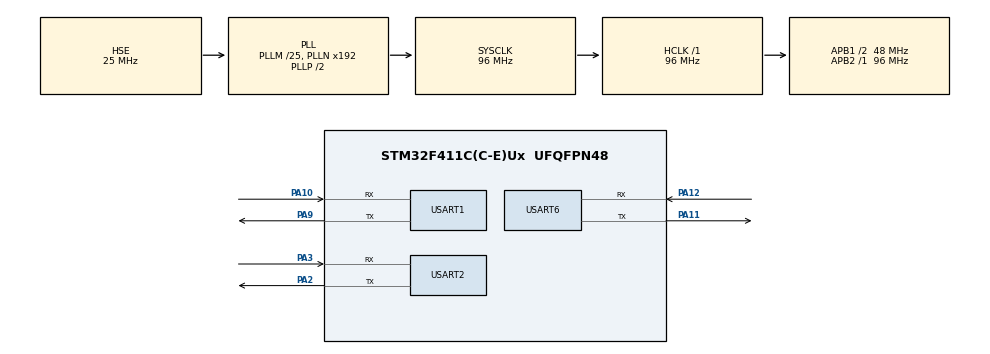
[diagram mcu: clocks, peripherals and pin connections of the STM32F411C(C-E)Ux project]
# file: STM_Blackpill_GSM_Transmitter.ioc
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Dma.Request0=USART1_TX
Dma.USART1_TX.0.Direction=DMA_MEMORY_TO_PERIPH
Dma.USART1_TX.0.FIFOMode=DMA_FIFOMODE_DISABLE
Dma.USART1_TX.0.Instance=DMA2_Stream7
Dma.USART1_TX.0.MemDataAlignment=DMA_MDATAALIGN_BYTE
Dma.USART1_TX.0.MemInc=DMA_MINC_ENABLE
Dma.USART1_TX.0.Mode=DMA_NORMAL
Dma.USART1_TX.0.PeriphDataAlignment=DMA_PDATAALIGN_BYTE
Dma.USART1_TX.0.PeriphInc=DMA_PINC_DISABLE
Dma.USART1_TX.0.Priority=DMA_PRIORITY_LOW
IWDG.Prescaler=IWDG_PRESCALER_64
IWDG.Reload=4000
Mcu.Family=STM32F4
Mcu.Name=STM32F411C(C-E)Ux
Mcu.Package=UFQFPN48
NVIC.DMA2_Stream7_IRQn=true\:0\:0\:false\:false\:true\:false\:true\:true
NVIC.PriorityGroup=NVIC_PRIORITYGROUP_4
NVIC.TIM2_IRQn=true\:0\:0\:false\:false\:true\:true\:true\:true
NVIC.USART1_IRQn=true\:0\:0\:false\:false\:true\:true\:true\:true
NVIC.USART2_IRQn=true\:0\:0\:false\:false\:true\:true\:true\:true
NVIC.USART6_IRQn=true\:0\:0\:false\:false\:true\:true\:true\:true
PA10.Mode=Asynchronous
PA10.Signal=USART1_RX
PA11.Mode=Asynchronous
PA11.Signal=USART6_TX
PA12.Mode=Asynchronous
PA12.Signal=USART6_RX
PA13.Mode=Serial_Wire
PA13.Signal=SYS_JTMS-SWDIO
PA14.Mode=Serial_Wire
PA14.Signal=SYS_JTCK-SWCLK
PA2.Mode=Asynchronous
PA2.Signal=USART2_TX
PA3.Mode=Asynchronous
PA3.Signal=USART2_RX
PA9.Mode=Asynchronous
PA9.Signal=USART1_TX
PH0\ -\ OSC_IN.Mode=HSE-External-Oscillator
PH0\ -\ OSC_IN.Signal=RCC_OSC_IN
PH1\ -\ OSC_OUT.Mode=HSE-External-Oscillator
PH1\ -\ OSC_OUT.Signal=RCC_OSC_OUT
ProjectManager.HeapSize=0x200
ProjectManager.StackSize=0x400
ProjectManager.TargetToolchain=STM32CubeIDE
RCC.48MHZClocksFreq_Value=48000000
RCC.AHBFreq_Value=96000000
RCC.APB1CLKDivider=RCC_HCLK_DIV2
RCC.APB1Freq_Value=48000000
RCC.APB1TimFreq_Value=96000000
RCC.APB2Freq_Value=96000000
RCC.APB2TimFreq_Value=96000000
RCC.CortexFreq_Value=96000000
RCC.HCLKFreq_Value=96000000
RCC.HSE_VALUE=25000000
RCC.HSI_VALUE=16000000
RCC.LSE_VALUE=32768
RCC.PLLM=25
RCC.PLLSourceVirtual=RCC_PLLSOURCE_HSE
RCC.SYSCLKFreq_VALUE=96000000
RCC.SYSCLKSource=RCC_SYSCLKSOURCE_PLLCLK
RCC.VCOOutputFreq_Value=192000000
TIM2.Period=9999
TIM2.Prescaler=9599
USART1.VirtualMode=VM_ASYNC
USART2.VirtualMode=VM_ASYNC
USART6.VirtualMode=VM_ASYNC
VP_IWDG_VS_IWDG.Mode=IWDG_Activate
VP_TIM2_VS_ClockSourceINT.Mode=Internal
board=custom

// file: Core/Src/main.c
/* USER CODE BEGIN Header */
/**
  ******************************************************************************
  * @file           : main.c
  * @brief          : Main program body
  ******************************************************************************
  * @attention
  *
  * Copyright (c) 2026 STMicroelectronics.
  * All rights reserved.
  *
  * This software is licensed under terms that can be found in the LICENSE file
  * in the root directory of this software component.
  * If no LICENSE file comes with this software, it is provided AS-IS.
  *
  ******************************************************************************
  */
/* USER CODE END Header */
#include "main.h"

/* USER CODE BEGIN Includes */
#include <stdio.h>
#include <string.h>
#include "tf02pro.h"
#include "gsm_mqtt.h"
#include "aws_manager.h"
#include "lora_tx.h"
#include "modem_gate.h"
/* USER CODE END Includes */

TIM_HandleTypeDef htim2;

UART_HandleTypeDef huart1;
UART_HandleTypeDef huart2;
UART_HandleTypeDef huart6;
DMA_HandleTypeDef hdma_usart1_tx;

void SystemClock_Config(void);
static void MX_GPIO_Init(void);
static void MX_DMA_Init(void);
static void MX_USART2_UART_Init(void);
static void MX_USART6_UART_Init(void);
static void MX_USART1_UART_Init(void);
static void MX_TIM2_Init(void);

int main(void)
{

  /* MCU Configuration--------------------------------------------------------*/

  /* Reset of all peripherals, Initializes the Flash interface and the Systick. */
  HAL_Init();

  /* Configure the system clock */
  SystemClock_Config();

  /* Initialize all configured peripherals */
  MX_GPIO_Init();
  MX_DMA_Init();
  MX_USART2_UART_Init();
  MX_USART6_UART_Init();
  MX_USART1_UART_Init();
  MX_TIM2_Init();

  /* USER CODE BEGIN 2 */
  /* Lidar + LoRa come up BEFORE the (blocking) AWS_Init() attempt below,
   * not after it: both are interrupt/DMA driven, so once started they keep
   * running while AWS_Init() sits in its long modem-boot / network-
   * registration / provisioning waits. With no SIM or no coverage that can
   * be minutes, and LoRa is the receiver's cellular-independent link to
   * this transmitter — it must be on the air from the first second. */
  TF02_Init(&huart6);
  LoRaTx_Init(&huart1);   /* TX-only broadcast on its own UART (USART1,
                              PA9/PA10, DMA2 Stream7); parses this unit's
                              number out of DEVICE_ID. */
  HAL_TIM_Base_Start_IT(&htim2);   /* 1Hz LoRa send from
                              HAL_TIM_PeriodElapsedCallback() below — fully
                              independent of the main loop, so a stalled
                              AWS_Init()/GSM call can never delay or skip a
                              broadcast (see lora_tx.h). Must run after
                              LoRaTx_Init() so the first interrupt (~1s
                              from now) always has a bound UART. */

  /* AWS_Init() itself is unchanged and still called exactly as before. It
   * is now only attempted when ModemGate_SimReady() says the modem is up
   * and a SIM is present — otherwise a silent modem or missing SIM would
   * burn a full blocking attempt (up to minutes) that can never succeed.
   * The retry block in the main loop below applies the same gate. */
  bool aws_inited = false;
  if (ModemGate_SimReady(&huart2))
  {
      aws_inited = AWS_Init(&huart2, "airtelgprs.com");
  }
  uint32_t lastAwsRetryTick = HAL_GetTick();
  uint32_t lastLidarSend = 0;
  /* USER CODE END 2 */

  /* Infinite loop */
  /* USER CODE BEGIN WHILE */
  while (1)
  {
      /* AWS_Init()'s return value used to be discarded entirely — if the
       * boot-time attempt failed (e.g. a transient LTE registration
       * hiccup), the device sent zero telemetry forever with no retry
       * until someone manually power-cycled it. Retry periodically
       * instead. Deliberately NOT using a blocking HAL_Delay() between
       * attempts (unlike the receiver's equivalent retry loop) — this
       * device's LiDAR read/publish below must keep running every
       * iteration regardless of GSM state, per this project's CRITICAL
       * CONSTRAINT in CLAUDE.md. AWS_Init() itself is still internally
       * blocking for the duration of a single attempt; this only avoids
       * adding extra dead time between attempts on top of that. */
      if (!aws_inited)
      {
          if (HAL_GetTick() - lastAwsRetryTick >= 5000U)
          {
              lastAwsRetryTick = HAL_GetTick();
              if (ModemGate_SimReady(&huart2))
              {
                  aws_inited = AWS_Init(&huart2, "airtelgprs.com");
              }
          }
      }
      else
      {
          GSM_MQTT_Poll();
          AWS_Manager_Tick(HAL_GetTick());
          /* Ensure Blue LED (PC13, active-low) is solid ON once connected */
          if (GSM_MQTT_IsConnected()) {
              HAL_GPIO_WritePin(GPIOC, GPIO_PIN_13, GPIO_PIN_RESET);
          }
      }

      uint16_t dist, strength;
      if (TF02_GetLatest(&dist, &strength)) {
          if (HAL_GetTick() - lastLidarSend >= 500) {   // 2 readings/sec (500ms) - optimal for LTE QoS 0
              if (GSM_MQTT_IsConnected()) {
                  AWS_PublishTelemetry(dist, 0, 0, false, 0, "OK");
              } else {
                  OfflineTelemetry_t rec;
                  rec.uptime_s = HAL_GetTick() / 1000U;
                  rec.distance_cm = dist;
                  rec.selected_target_id = 0;
                  rec.battery_pct = 100;
                  rec.is_charging = false;
                  rec.gsm_rssi = 0;
                  strncpy(rec.link_state, "LORA", sizeof(rec.link_state) - 1);
                  rec.link_state[sizeof(rec.link_state) - 1] = '\0';
                  rec.is_lora = false;
                  AWS_OfflineQueue_Push(&rec);
              }
              lastLidarSend = HAL_GetTick();
          }
      }
  }
    /* USER CODE END WHILE */

  }

void SystemClock_Config(void)
{
  RCC_OscInitTypeDef RCC_OscInitStruct = {0};
  RCC_ClkInitTypeDef RCC_ClkInitStruct = {0};

  /** Configure the main internal regulator output voltage
  */
  __HAL_RCC_PWR_CLK_ENABLE();
  __HAL_PWR_VOLTAGESCALING_CONFIG(PWR_REGULATOR_VOLTAGE_SCALE1);

  /** Initializes the RCC Oscillators according to the specified parameters
  * in the RCC_OscInitTypeDef structure.
  */
  RCC_OscInitStruct.OscillatorType = RCC_OSCILLATORTYPE_HSE;
  RCC_OscInitStruct.HSEState = RCC_HSE_ON;
  RCC_OscInitStruct.PLL.PLLState = RCC_PLL_ON;
  RCC_OscInitStruct.PLL.PLLSource = RCC_PLLSOURCE_HSE;
  RCC_OscInitStruct.PLL.PLLM = 25;
  RCC_OscInitStruct.PLL.PLLN = 192;
  RCC_OscInitStruct.PLL.PLLP = RCC_PLLP_DIV2;
  RCC_OscInitStruct.PLL.PLLQ = 4;
  if (HAL_RCC_OscConfig(&RCC_OscInitStruct) != HAL_OK)
  {
    Error_Handler();
  }

  /** Initializes the CPU, AHB and APB buses clocks
  */
  RCC_ClkInitStruct.ClockType = RCC_CLOCKTYPE_HCLK|RCC_CLOCKTYPE_SYSCLK
                              |RCC_CLOCKTYPE_PCLK1|RCC_CLOCKTYPE_PCLK2;
  RCC_ClkInitStruct.SYSCLKSource = RCC_SYSCLKSOURCE_PLLCLK;
  RCC_ClkInitStruct.AHBCLKDivider = RCC_SYSCLK_DIV1;
  RCC_ClkInitStruct.APB1CLKDivider = RCC_HCLK_DIV2;
  RCC_ClkInitStruct.APB2CLKDivider = RCC_HCLK_DIV1;

  if (HAL_RCC_ClockConfig(&RCC_ClkInitStruct, FLASH_LATENCY_3) != HAL_OK)
  {
    Error_Handler();
  }
}

static void MX_TIM2_Init(void)
{

  TIM_ClockConfigTypeDef sClockSourceConfig = {0};
  TIM_MasterConfigTypeDef sMasterConfig = {0};

  htim2.Instance = TIM2;
  htim2.Init.Prescaler = 9599;
  htim2.Init.CounterMode = TIM_COUNTERMODE_UP;
  htim2.Init.Period = 9999;
  htim2.Init.ClockDivision = TIM_CLOCKDIVISION_DIV1;
  htim2.Init.AutoReloadPreload = TIM_AUTORELOAD_PRELOAD_DISABLE;
  if (HAL_TIM_Base_Init(&htim2) != HAL_OK)
  {
    Error_Handler();
  }
  sClockSourceConfig.ClockSource = TIM_CLOCKSOURCE_INTERNAL;
  if (HAL_TIM_ConfigClockSource(&htim2, &sClockSourceConfig) != HAL_OK)
  {
    Error_Handler();
  }
  sMasterConfig.MasterOutputTrigger = TIM_TRGO_RESET;
  sMasterConfig.MasterSlaveMode = TIM_MASTERSLAVEMODE_DISABLE;
  if (HAL_TIMEx_MasterConfigSynchronization(&htim2, &sMasterConfig) != HAL_OK)
  {
    Error_Handler();
  }

}

static void MX_USART1_UART_Init(void)
{

  huart1.Instance = USART1;
  huart1.Init.BaudRate = 115200;
  huart1.Init.WordLength = UART_WORDLENGTH_8B;
  huart1.Init.StopBits = UART_STOPBITS_1;
  huart1.Init.Parity = UART_PARITY_NONE;
  huart1.Init.Mode = UART_MODE_TX_RX;
  huart1.Init.HwFlowCtl = UART_HWCONTROL_NONE;
  huart1.Init.OverSampling = UART_OVERSAMPLING_16;
  if (HAL_UART_Init(&huart1) != HAL_OK)
  {
    Error_Handler();
  }

}

static void MX_USART2_UART_Init(void)
{

  huart2.Instance = USART2;
  huart2.Init.BaudRate = 115200;
  huart2.Init.WordLength = UART_WORDLENGTH_8B;
  huart2.Init.StopBits = UART_STOPBITS_1;
  huart2.Init.Parity = UART_PARITY_NONE;
  huart2.Init.Mode = UART_MODE_TX_RX;
  huart2.Init.HwFlowCtl = UART_HWCONTROL_NONE;
  huart2.Init.OverSampling = UART_OVERSAMPLING_16;
  if (HAL_UART_Init(&huart2) != HAL_OK)
  {
    Error_Handler();
  }

}

static void MX_USART6_UART_Init(void)
{

  huart6.Instance = USART6;
  huart6.Init.BaudRate = 115200;
  huart6.Init.WordLength = UART_WORDLENGTH_8B;
  huart6.Init.StopBits = UART_STOPBITS_1;
  huart6.Init.Parity = UART_PARITY_NONE;
  huart6.Init.Mode = UART_MODE_TX_RX;
  huart6.Init.HwFlowCtl = UART_HWCONTROL_NONE;
  huart6.Init.OverSampling = UART_OVERSAMPLING_16;
  if (HAL_UART_Init(&huart6) != HAL_OK)
  {
    Error_Handler();
  }

}

static void MX_DMA_Init(void)
{

  /* DMA controller clock enable */
  __HAL_RCC_DMA2_CLK_ENABLE();

  /* DMA interrupt init */
  /* DMA2_Stream7_IRQn interrupt configuration */
  HAL_NVIC_SetPriority(DMA2_Stream7_IRQn, 0, 0);
  HAL_NVIC_EnableIRQ(DMA2_Stream7_IRQn);

}

static void MX_GPIO_Init(void)
{
  GPIO_InitTypeDef GPIO_InitStruct = {0};

  /* GPIO Ports Clock Enable */
  __HAL_RCC_GPIOC_CLK_ENABLE();
  __HAL_RCC_GPIOH_CLK_ENABLE();
  __HAL_RCC_GPIOA_CLK_ENABLE();

  /* Configure GPIO pin Output Level for PC13 (Blue LED, active low) */
  HAL_GPIO_WritePin(GPIOC, GPIO_PIN_13, GPIO_PIN_RESET);

  /* Configure GPIO pin : PC13 */
  GPIO_InitStruct.Pin = GPIO_PIN_13;
  GPIO_InitStruct.Mode = GPIO_MODE_OUTPUT_PP;
  GPIO_InitStruct.Pull = GPIO_NOPULL;
  GPIO_InitStruct.Speed = GPIO_SPEED_FREQ_LOW;
  HAL_GPIO_Init(GPIOC, &GPIO_InitStruct);

  /* Configure GPIO pin Output Level for PA1/PA4 (LoRa M1/M0, LOW=Normal Mode) and PA5/PA8 (Power/Enable, HIGH) */
  HAL_GPIO_WritePin(GPIOA, GPIO_PIN_1|GPIO_PIN_4, GPIO_PIN_RESET);
  HAL_GPIO_WritePin(GPIOA, GPIO_PIN_5|GPIO_PIN_8, GPIO_PIN_SET);

  /* Configure GPIO pins : PA1 PA4 PA5 PA8 */
  GPIO_InitStruct.Pin = GPIO_PIN_1|GPIO_PIN_4|GPIO_PIN_5|GPIO_PIN_8;
  GPIO_InitStruct.Mode = GPIO_MODE_OUTPUT_PP;
  GPIO_InitStruct.Pull = GPIO_NOPULL;
  GPIO_InitStruct.Speed = GPIO_SPEED_FREQ_LOW;
  HAL_GPIO_Init(GPIOA, &GPIO_InitStruct);

  HAL_GPIO_WritePin(GPIOA, GPIO_PIN_5, GPIO_PIN_SET);
}

/* USER CODE BEGIN 4 */
void HAL_UART_RxCpltCallback(UART_HandleTypeDef *huart) {
    if (huart->Instance == USART6) {
        TF02_RxCpltHandler(huart);
    }
}

void HAL_UART_ErrorCallback(UART_HandleTypeDef *huart) {
    if (huart->Instance == USART6) {
        __HAL_UART_CLEAR_OREFLAG(huart);
        __HAL_UART_CLEAR_NEFLAG(huart);
        __HAL_UART_CLEAR_FEFLAG(huart);
        __HAL_UART_CLEAR_PEFLAG(huart);
        TF02_RxCpltHandler(huart);
    }
}

/* Fires once a second, forever, from TIM2 — see lora_tx.h's header comment
 * and the HAL_TIM_Base_Start_IT(&htim2) call site above for the full
 * reasoning. Deliberately minimal: LoRaTx_Tick() itself only builds a small
 * buffer and kicks off a DMA transfer (HAL_UART_Transmit_DMA()), it never
 * blocks — so this interrupt handler finishes in a few microseconds
 * regardless of what the main loop (AWS_Init()/GSM included) is doing. */
void HAL_TIM_PeriodElapsedCallback(TIM_HandleTypeDef *htim) {
    if (htim->Instance == TIM2) {
        LoRaTx_Tick();
    }
}

/* __io_putchar was declared `extern ... __attribute__((weak))` in
 * syscalls.c with no definition anywhere in this project (the USB-CDC
 * console it used to route through in the reference project was never
 * ported here). An unresolved weak symbol resolves to address 0, so any
 * code path that actually reaches real printf()/vprintf() (e.g. logger.c's
 * log_print(), used by cmd_router.c/device_sm.c if those are ever wired
 * into main()) would call through a null function pointer and HardFault
 * the MCU. This project's CLAUDE.md also requires no debug output of any
 * kind — this stub satisfies both: it's safe to call, and it transmits
 * nothing. aws_manager.c's own `#define printf dbg` and gsm_mqtt.c's dbg()
 * are unaffected either way (dbg() never reaches this path at all). */
int __io_putchar(int ch)
{
    (void)ch;
    return ch;
}
/* USER CODE END 4 */

void Error_Handler(void)
{
  __disable_irq();
  while (1)
  {
  }
}
